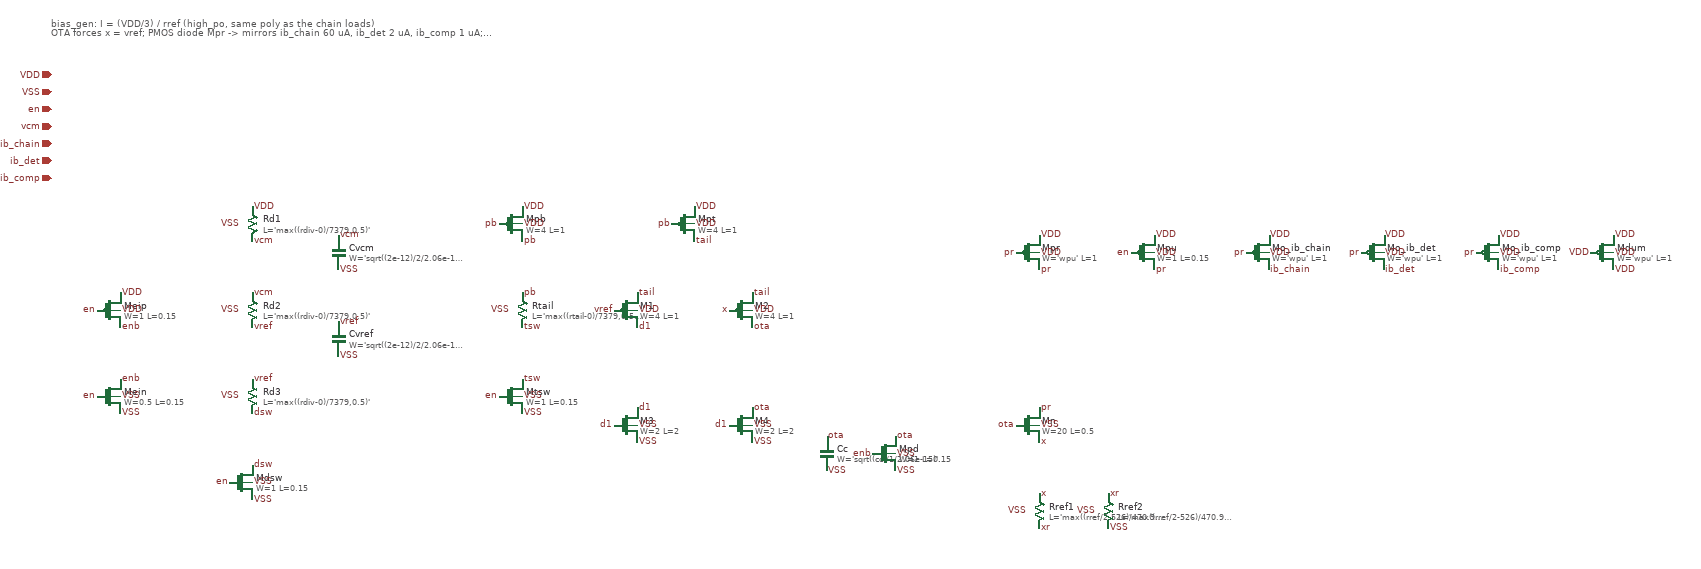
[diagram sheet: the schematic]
v {xschem version=3.4.5 file_version=1.2
}
G {}
K {}
V {}
S {}
E {}
T {bias_gen: I = (VDD/3) / rref (high_po, same poly as the chain loads)
OTA forces x = vref; PMOS diode Mpr -> mirrors ib_chain 60 uA, ib_det 2 uA, ib_comp 1 uA; vcm = 2 VDD/3. en = 0: all off} -800 -860 0 0 0.4 0.4 {}
C {devices/iopin.sym} -800 -760 0 0 {name=p1
lab=VDD}
C {devices/iopin.sym} -800 -730 0 0 {name=p2
lab=VSS}
C {devices/iopin.sym} -800 -700 0 0 {name=p3
lab=en}
C {devices/iopin.sym} -800 -670 0 0 {name=p4
lab=vcm}
C {devices/iopin.sym} -800 -640 0 0 {name=p5
lab=ib_chain}
C {devices/iopin.sym} -800 -610 0 0 {name=p6
lab=ib_det}
C {devices/iopin.sym} -800 -580 0 0 {name=p7
lab=ib_comp}
C {sky130_fd_pr/pfet_01v8.sym} -700 -350 0 0 {name=Meip
nf=1
mult=1
ad="'int((nf+1)/2) * W/nf * 0.29'"
pd="'2*int((nf+1)/2) * (W/nf + 0.29)'"
as="'int((nf+2)/2) * W/nf * 0.29'"
ps="'2*int((nf+2)/2) * (W/nf + 0.29)'"
nrd="'0.29 / W'"
nrs="'0.29 / W'"
sa=0
sb=0
sd=0
L=0.15
W=1
model=pfet_01v8
spiceprefix=X}
C {devices/lab_pin.sym} -680 -320 0 1 {name=p8
sig_type=std_logic
lab=enb}
C {devices/lab_pin.sym} -720 -350 0 0 {name=p9
sig_type=std_logic
lab=en}
C {devices/lab_pin.sym} -680 -380 0 1 {name=p10
sig_type=std_logic
lab=VDD}
C {devices/lab_pin.sym} -680 -350 0 1 {name=p11
sig_type=std_logic
lab=VDD}
C {sky130_fd_pr/nfet_01v8.sym} -700 -200 0 0 {name=Mein
nf=1
mult=1
ad="'int((nf+1)/2) * W/nf * 0.29'"
pd="'2*int((nf+1)/2) * (W/nf + 0.29)'"
as="'int((nf+2)/2) * W/nf * 0.29'"
ps="'2*int((nf+2)/2) * (W/nf + 0.29)'"
nrd="'0.29 / W'"
nrs="'0.29 / W'"
sa=0
sb=0
sd=0
L=0.15
W=0.5
model=nfet_01v8
spiceprefix=X}
C {devices/lab_pin.sym} -680 -230 0 1 {name=p12
sig_type=std_logic
lab=enb}
C {devices/lab_pin.sym} -720 -200 0 0 {name=p13
sig_type=std_logic
lab=en}
C {devices/lab_pin.sym} -680 -170 0 1 {name=p14
sig_type=std_logic
lab=VSS}
C {devices/lab_pin.sym} -680 -200 0 1 {name=p15
sig_type=std_logic
lab=VSS}
C {sky130_fd_pr/res_xhigh_po_0p35.sym} -450 -500 0 0 {name=Rd1
L='max((rdiv-0)/7379,0.5)'
model=res_xhigh_po_0p35
mult=1
spiceprefix=X}
C {devices/lab_pin.sym} -450 -530 0 1 {name=p16
sig_type=std_logic
lab=VDD}
C {devices/lab_pin.sym} -450 -470 0 1 {name=p17
sig_type=std_logic
lab=vcm}
C {devices/lab_pin.sym} -470 -500 0 0 {name=p18
sig_type=std_logic
lab=VSS}
C {sky130_fd_pr/res_xhigh_po_0p35.sym} -450 -350 0 0 {name=Rd2
L='max((rdiv-0)/7379,0.5)'
model=res_xhigh_po_0p35
mult=1
spiceprefix=X}
C {devices/lab_pin.sym} -450 -380 0 1 {name=p19
sig_type=std_logic
lab=vcm}
C {devices/lab_pin.sym} -450 -320 0 1 {name=p20
sig_type=std_logic
lab=vref}
C {devices/lab_pin.sym} -470 -350 0 0 {name=p21
sig_type=std_logic
lab=VSS}
C {sky130_fd_pr/res_xhigh_po_0p35.sym} -450 -200 0 0 {name=Rd3
L='max((rdiv-0)/7379,0.5)'
model=res_xhigh_po_0p35
mult=1
spiceprefix=X}
C {devices/lab_pin.sym} -450 -230 0 1 {name=p22
sig_type=std_logic
lab=vref}
C {devices/lab_pin.sym} -450 -170 0 1 {name=p23
sig_type=std_logic
lab=dsw}
C {devices/lab_pin.sym} -470 -200 0 0 {name=p24
sig_type=std_logic
lab=VSS}
C {sky130_fd_pr/nfet_01v8.sym} -470 -50 0 0 {name=Mdsw
nf=1
mult=1
ad="'int((nf+1)/2) * W/nf * 0.29'"
pd="'2*int((nf+1)/2) * (W/nf + 0.29)'"
as="'int((nf+2)/2) * W/nf * 0.29'"
ps="'2*int((nf+2)/2) * (W/nf + 0.29)'"
nrd="'0.29 / W'"
nrs="'0.29 / W'"
sa=0
sb=0
sd=0
L=0.15
W=1
model=nfet_01v8
spiceprefix=X}
C {devices/lab_pin.sym} -450 -80 0 1 {name=p25
sig_type=std_logic
lab=dsw}
C {devices/lab_pin.sym} -490 -50 0 0 {name=p26
sig_type=std_logic
lab=en}
C {devices/lab_pin.sym} -450 -20 0 1 {name=p27
sig_type=std_logic
lab=VSS}
C {devices/lab_pin.sym} -450 -50 0 1 {name=p28
sig_type=std_logic
lab=VSS}
C {sky130_fd_pr/cap_mim_m3_1.sym} -300 -450 0 0 {name=Cvcm
model=cap_mim_m3_1
W='sqrt((2e-12)/2/2.06e-15)'
L='sqrt((2e-12)/2/2.06e-15)'
MF=2
spiceprefix=X}
C {devices/lab_pin.sym} -300 -480 0 1 {name=p29
sig_type=std_logic
lab=vcm}
C {devices/lab_pin.sym} -300 -420 0 1 {name=p30
sig_type=std_logic
lab=VSS}
C {sky130_fd_pr/cap_mim_m3_1.sym} -300 -300 0 0 {name=Cvref
model=cap_mim_m3_1
W='sqrt((2e-12)/2/2.06e-15)'
L='sqrt((2e-12)/2/2.06e-15)'
MF=2
spiceprefix=X}
C {devices/lab_pin.sym} -300 -330 0 1 {name=p31
sig_type=std_logic
lab=vref}
C {devices/lab_pin.sym} -300 -270 0 1 {name=p32
sig_type=std_logic
lab=VSS}
C {sky130_fd_pr/pfet_01v8.sym} 0 -500 0 0 {name=Mpb
nf=1
mult=1
ad="'int((nf+1)/2) * W/nf * 0.29'"
pd="'2*int((nf+1)/2) * (W/nf + 0.29)'"
as="'int((nf+2)/2) * W/nf * 0.29'"
ps="'2*int((nf+2)/2) * (W/nf + 0.29)'"
nrd="'0.29 / W'"
nrs="'0.29 / W'"
sa=0
sb=0
sd=0
L=1
W=4
model=pfet_01v8
spiceprefix=X}
C {devices/lab_pin.sym} 20 -470 0 1 {name=p33
sig_type=std_logic
lab=pb}
C {devices/lab_pin.sym} -20 -500 0 0 {name=p34
sig_type=std_logic
lab=pb}
C {devices/lab_pin.sym} 20 -530 0 1 {name=p35
sig_type=std_logic
lab=VDD}
C {devices/lab_pin.sym} 20 -500 0 1 {name=p36
sig_type=std_logic
lab=VDD}
C {sky130_fd_pr/res_xhigh_po_0p35.sym} 20 -350 0 0 {name=Rtail
L='max((rtail-0)/7379,0.5)'
model=res_xhigh_po_0p35
mult=1
spiceprefix=X}
C {devices/lab_pin.sym} 20 -380 0 1 {name=p37
sig_type=std_logic
lab=pb}
C {devices/lab_pin.sym} 20 -320 0 1 {name=p38
sig_type=std_logic
lab=tsw}
C {devices/lab_pin.sym} 0 -350 0 0 {name=p39
sig_type=std_logic
lab=VSS}
C {sky130_fd_pr/nfet_01v8.sym} 0 -200 0 0 {name=Mtsw
nf=1
mult=1
ad="'int((nf+1)/2) * W/nf * 0.29'"
pd="'2*int((nf+1)/2) * (W/nf + 0.29)'"
as="'int((nf+2)/2) * W/nf * 0.29'"
ps="'2*int((nf+2)/2) * (W/nf + 0.29)'"
nrd="'0.29 / W'"
nrs="'0.29 / W'"
sa=0
sb=0
sd=0
L=0.15
W=1
model=nfet_01v8
spiceprefix=X}
C {devices/lab_pin.sym} 20 -230 0 1 {name=p40
sig_type=std_logic
lab=tsw}
C {devices/lab_pin.sym} -20 -200 0 0 {name=p41
sig_type=std_logic
lab=en}
C {devices/lab_pin.sym} 20 -170 0 1 {name=p42
sig_type=std_logic
lab=VSS}
C {devices/lab_pin.sym} 20 -200 0 1 {name=p43
sig_type=std_logic
lab=VSS}
C {sky130_fd_pr/pfet_01v8.sym} 300 -500 0 0 {name=Mpt
nf=1
mult=1
ad="'int((nf+1)/2) * W/nf * 0.29'"
pd="'2*int((nf+1)/2) * (W/nf + 0.29)'"
as="'int((nf+2)/2) * W/nf * 0.29'"
ps="'2*int((nf+2)/2) * (W/nf + 0.29)'"
nrd="'0.29 / W'"
nrs="'0.29 / W'"
sa=0
sb=0
sd=0
L=1
W=4
model=pfet_01v8
spiceprefix=X}
C {devices/lab_pin.sym} 320 -470 0 1 {name=p44
sig_type=std_logic
lab=tail}
C {devices/lab_pin.sym} 280 -500 0 0 {name=p45
sig_type=std_logic
lab=pb}
C {devices/lab_pin.sym} 320 -530 0 1 {name=p46
sig_type=std_logic
lab=VDD}
C {devices/lab_pin.sym} 320 -500 0 1 {name=p47
sig_type=std_logic
lab=VDD}
C {sky130_fd_pr/pfet_01v8.sym} 200 -350 0 0 {name=M1
nf=1
mult=1
ad="'int((nf+1)/2) * W/nf * 0.29'"
pd="'2*int((nf+1)/2) * (W/nf + 0.29)'"
as="'int((nf+2)/2) * W/nf * 0.29'"
ps="'2*int((nf+2)/2) * (W/nf + 0.29)'"
nrd="'0.29 / W'"
nrs="'0.29 / W'"
sa=0
sb=0
sd=0
L=1
W=4
model=pfet_01v8
spiceprefix=X}
C {devices/lab_pin.sym} 220 -320 0 1 {name=p48
sig_type=std_logic
lab=d1}
C {devices/lab_pin.sym} 180 -350 0 0 {name=p49
sig_type=std_logic
lab=vref}
C {devices/lab_pin.sym} 220 -380 0 1 {name=p50
sig_type=std_logic
lab=tail}
C {devices/lab_pin.sym} 220 -350 0 1 {name=p51
sig_type=std_logic
lab=VDD}
C {sky130_fd_pr/pfet_01v8.sym} 400 -350 0 0 {name=M2
nf=1
mult=1
ad="'int((nf+1)/2) * W/nf * 0.29'"
pd="'2*int((nf+1)/2) * (W/nf + 0.29)'"
as="'int((nf+2)/2) * W/nf * 0.29'"
ps="'2*int((nf+2)/2) * (W/nf + 0.29)'"
nrd="'0.29 / W'"
nrs="'0.29 / W'"
sa=0
sb=0
sd=0
L=1
W=4
model=pfet_01v8
spiceprefix=X}
C {devices/lab_pin.sym} 420 -320 0 1 {name=p52
sig_type=std_logic
lab=ota}
C {devices/lab_pin.sym} 380 -350 0 0 {name=p53
sig_type=std_logic
lab=x}
C {devices/lab_pin.sym} 420 -380 0 1 {name=p54
sig_type=std_logic
lab=tail}
C {devices/lab_pin.sym} 420 -350 0 1 {name=p55
sig_type=std_logic
lab=VDD}
C {sky130_fd_pr/nfet_01v8.sym} 200 -150 0 0 {name=M3
nf=1
mult=1
ad="'int((nf+1)/2) * W/nf * 0.29'"
pd="'2*int((nf+1)/2) * (W/nf + 0.29)'"
as="'int((nf+2)/2) * W/nf * 0.29'"
ps="'2*int((nf+2)/2) * (W/nf + 0.29)'"
nrd="'0.29 / W'"
nrs="'0.29 / W'"
sa=0
sb=0
sd=0
L=2
W=2
model=nfet_01v8
spiceprefix=X}
C {devices/lab_pin.sym} 220 -180 0 1 {name=p56
sig_type=std_logic
lab=d1}
C {devices/lab_pin.sym} 180 -150 0 0 {name=p57
sig_type=std_logic
lab=d1}
C {devices/lab_pin.sym} 220 -120 0 1 {name=p58
sig_type=std_logic
lab=VSS}
C {devices/lab_pin.sym} 220 -150 0 1 {name=p59
sig_type=std_logic
lab=VSS}
C {sky130_fd_pr/nfet_01v8.sym} 400 -150 0 0 {name=M4
nf=1
mult=1
ad="'int((nf+1)/2) * W/nf * 0.29'"
pd="'2*int((nf+1)/2) * (W/nf + 0.29)'"
as="'int((nf+2)/2) * W/nf * 0.29'"
ps="'2*int((nf+2)/2) * (W/nf + 0.29)'"
nrd="'0.29 / W'"
nrs="'0.29 / W'"
sa=0
sb=0
sd=0
L=2
W=2
model=nfet_01v8
spiceprefix=X}
C {devices/lab_pin.sym} 420 -180 0 1 {name=p60
sig_type=std_logic
lab=ota}
C {devices/lab_pin.sym} 380 -150 0 0 {name=p61
sig_type=std_logic
lab=d1}
C {devices/lab_pin.sym} 420 -120 0 1 {name=p62
sig_type=std_logic
lab=VSS}
C {devices/lab_pin.sym} 420 -150 0 1 {name=p63
sig_type=std_logic
lab=VSS}
C {sky130_fd_pr/cap_mim_m3_1.sym} 550 -100 0 0 {name=Cc
model=cap_mim_m3_1
W='sqrt((cc)/1/2.06e-15)'
L='sqrt((cc)/1/2.06e-15)'
MF=1
spiceprefix=X}
C {devices/lab_pin.sym} 550 -130 0 1 {name=p64
sig_type=std_logic
lab=ota}
C {devices/lab_pin.sym} 550 -70 0 1 {name=p65
sig_type=std_logic
lab=VSS}
C {sky130_fd_pr/nfet_01v8.sym} 650 -100 0 0 {name=Mpd
nf=1
mult=1
ad="'int((nf+1)/2) * W/nf * 0.29'"
pd="'2*int((nf+1)/2) * (W/nf + 0.29)'"
as="'int((nf+2)/2) * W/nf * 0.29'"
ps="'2*int((nf+2)/2) * (W/nf + 0.29)'"
nrd="'0.29 / W'"
nrs="'0.29 / W'"
sa=0
sb=0
sd=0
L=0.15
W=1
model=nfet_01v8
spiceprefix=X}
C {devices/lab_pin.sym} 670 -130 0 1 {name=p66
sig_type=std_logic
lab=ota}
C {devices/lab_pin.sym} 630 -100 0 0 {name=p67
sig_type=std_logic
lab=enb}
C {devices/lab_pin.sym} 670 -70 0 1 {name=p68
sig_type=std_logic
lab=VSS}
C {devices/lab_pin.sym} 670 -100 0 1 {name=p69
sig_type=std_logic
lab=VSS}
C {sky130_fd_pr/nfet_01v8.sym} 900 -150 0 0 {name=Mn
nf=2
mult=1
ad="'int((nf+1)/2) * W/nf * 0.29'"
pd="'2*int((nf+1)/2) * (W/nf + 0.29)'"
as="'int((nf+2)/2) * W/nf * 0.29'"
ps="'2*int((nf+2)/2) * (W/nf + 0.29)'"
nrd="'0.29 / W'"
nrs="'0.29 / W'"
sa=0
sb=0
sd=0
L=0.5
W=20
model=nfet_01v8
spiceprefix=X}
C {devices/lab_pin.sym} 920 -180 0 1 {name=p70
sig_type=std_logic
lab=pr}
C {devices/lab_pin.sym} 880 -150 0 0 {name=p71
sig_type=std_logic
lab=ota}
C {devices/lab_pin.sym} 920 -120 0 1 {name=p72
sig_type=std_logic
lab=x}
C {devices/lab_pin.sym} 920 -150 0 1 {name=p73
sig_type=std_logic
lab=VSS}
C {sky130_fd_pr/res_high_po_0p69.sym} 920 0 0 0 {name=Rref1
L='max((rref/2-526)/470.9,0.5)'
model=res_high_po_0p69
mult=1
spiceprefix=X}
C {devices/lab_pin.sym} 920 -30 0 1 {name=p74
sig_type=std_logic
lab=x}
C {devices/lab_pin.sym} 920 30 0 1 {name=p75
sig_type=std_logic
lab=xr}
C {devices/lab_pin.sym} 900 0 0 0 {name=p76
sig_type=std_logic
lab=VSS}
C {sky130_fd_pr/res_high_po_0p69.sym} 1040 0 0 0 {name=Rref2
L='max((rref/2-526)/470.9,0.5)'
model=res_high_po_0p69
mult=1
spiceprefix=X}
C {devices/lab_pin.sym} 1040 -30 0 1 {name=p77
sig_type=std_logic
lab=xr}
C {devices/lab_pin.sym} 1040 30 0 1 {name=p78
sig_type=std_logic
lab=VSS}
C {devices/lab_pin.sym} 1020 0 0 0 {name=p79
sig_type=std_logic
lab=VSS}
C {sky130_fd_pr/pfet_01v8.sym} 900 -450 0 0 {name=Mpr
nf=1
mult=60
ad="'int((nf+1)/2) * W/nf * 0.29'"
pd="'2*int((nf+1)/2) * (W/nf + 0.29)'"
as="'int((nf+2)/2) * W/nf * 0.29'"
ps="'2*int((nf+2)/2) * (W/nf + 0.29)'"
nrd="'0.29 / W'"
nrs="'0.29 / W'"
sa=0
sb=0
sd=0
L=1
W='wpu'
model=pfet_01v8
spiceprefix=X}
C {devices/lab_pin.sym} 920 -420 0 1 {name=p80
sig_type=std_logic
lab=pr}
C {devices/lab_pin.sym} 880 -450 0 0 {name=p81
sig_type=std_logic
lab=pr}
C {devices/lab_pin.sym} 920 -480 0 1 {name=p82
sig_type=std_logic
lab=VDD}
C {devices/lab_pin.sym} 920 -450 0 1 {name=p83
sig_type=std_logic
lab=VDD}
C {sky130_fd_pr/pfet_01v8.sym} 1100 -450 0 0 {name=Mpu
nf=1
mult=1
ad="'int((nf+1)/2) * W/nf * 0.29'"
pd="'2*int((nf+1)/2) * (W/nf + 0.29)'"
as="'int((nf+2)/2) * W/nf * 0.29'"
ps="'2*int((nf+2)/2) * (W/nf + 0.29)'"
nrd="'0.29 / W'"
nrs="'0.29 / W'"
sa=0
sb=0
sd=0
L=0.15
W=1
model=pfet_01v8
spiceprefix=X}
C {devices/lab_pin.sym} 1120 -420 0 1 {name=p84
sig_type=std_logic
lab=pr}
C {devices/lab_pin.sym} 1080 -450 0 0 {name=p85
sig_type=std_logic
lab=en}
C {devices/lab_pin.sym} 1120 -480 0 1 {name=p86
sig_type=std_logic
lab=VDD}
C {devices/lab_pin.sym} 1120 -450 0 1 {name=p87
sig_type=std_logic
lab=VDD}
C {sky130_fd_pr/pfet_01v8.sym} 1300 -450 0 0 {name=Mo_ib_chain
nf=1
mult=60
ad="'int((nf+1)/2) * W/nf * 0.29'"
pd="'2*int((nf+1)/2) * (W/nf + 0.29)'"
as="'int((nf+2)/2) * W/nf * 0.29'"
ps="'2*int((nf+2)/2) * (W/nf + 0.29)'"
nrd="'0.29 / W'"
nrs="'0.29 / W'"
sa=0
sb=0
sd=0
L=1
W='wpu'
model=pfet_01v8
spiceprefix=X}
C {devices/lab_pin.sym} 1320 -420 0 1 {name=p88
sig_type=std_logic
lab=ib_chain}
C {devices/lab_pin.sym} 1280 -450 0 0 {name=p89
sig_type=std_logic
lab=pr}
C {devices/lab_pin.sym} 1320 -480 0 1 {name=p90
sig_type=std_logic
lab=VDD}
C {devices/lab_pin.sym} 1320 -450 0 1 {name=p91
sig_type=std_logic
lab=VDD}
C {sky130_fd_pr/pfet_01v8.sym} 1500 -450 0 0 {name=Mo_ib_det
nf=1
mult=2
ad="'int((nf+1)/2) * W/nf * 0.29'"
pd="'2*int((nf+1)/2) * (W/nf + 0.29)'"
as="'int((nf+2)/2) * W/nf * 0.29'"
ps="'2*int((nf+2)/2) * (W/nf + 0.29)'"
nrd="'0.29 / W'"
nrs="'0.29 / W'"
sa=0
sb=0
sd=0
L=1
W='wpu'
model=pfet_01v8
spiceprefix=X}
C {devices/lab_pin.sym} 1520 -420 0 1 {name=p92
sig_type=std_logic
lab=ib_det}
C {devices/lab_pin.sym} 1480 -450 0 0 {name=p93
sig_type=std_logic
lab=pr}
C {devices/lab_pin.sym} 1520 -480 0 1 {name=p94
sig_type=std_logic
lab=VDD}
C {devices/lab_pin.sym} 1520 -450 0 1 {name=p95
sig_type=std_logic
lab=VDD}
C {sky130_fd_pr/pfet_01v8.sym} 1700 -450 0 0 {name=Mo_ib_comp
nf=1
mult=1
ad="'int((nf+1)/2) * W/nf * 0.29'"
pd="'2*int((nf+1)/2) * (W/nf + 0.29)'"
as="'int((nf+2)/2) * W/nf * 0.29'"
ps="'2*int((nf+2)/2) * (W/nf + 0.29)'"
nrd="'0.29 / W'"
nrs="'0.29 / W'"
sa=0
sb=0
sd=0
L=1
W='wpu'
model=pfet_01v8
spiceprefix=X}
C {devices/lab_pin.sym} 1720 -420 0 1 {name=p96
sig_type=std_logic
lab=ib_comp}
C {devices/lab_pin.sym} 1680 -450 0 0 {name=p97
sig_type=std_logic
lab=pr}
C {devices/lab_pin.sym} 1720 -480 0 1 {name=p98
sig_type=std_logic
lab=VDD}
C {devices/lab_pin.sym} 1720 -450 0 1 {name=p99
sig_type=std_logic
lab=VDD}
C {sky130_fd_pr/pfet_01v8.sym} 1900 -450 0 0 {name=Mdum
nf=1
mult=5
ad="'int((nf+1)/2) * W/nf * 0.29'"
pd="'2*int((nf+1)/2) * (W/nf + 0.29)'"
as="'int((nf+2)/2) * W/nf * 0.29'"
ps="'2*int((nf+2)/2) * (W/nf + 0.29)'"
nrd="'0.29 / W'"
nrs="'0.29 / W'"
sa=0
sb=0
sd=0
L=1
W='wpu'
model=pfet_01v8
spiceprefix=X}
C {devices/lab_pin.sym} 1920 -420 0 1 {name=p100
sig_type=std_logic
lab=VDD}
C {devices/lab_pin.sym} 1880 -450 0 0 {name=p101
sig_type=std_logic
lab=VDD}
C {devices/lab_pin.sym} 1920 -480 0 1 {name=p102
sig_type=std_logic
lab=VDD}
C {devices/lab_pin.sym} 1920 -450 0 1 {name=p103
sig_type=std_logic
lab=VDD}
